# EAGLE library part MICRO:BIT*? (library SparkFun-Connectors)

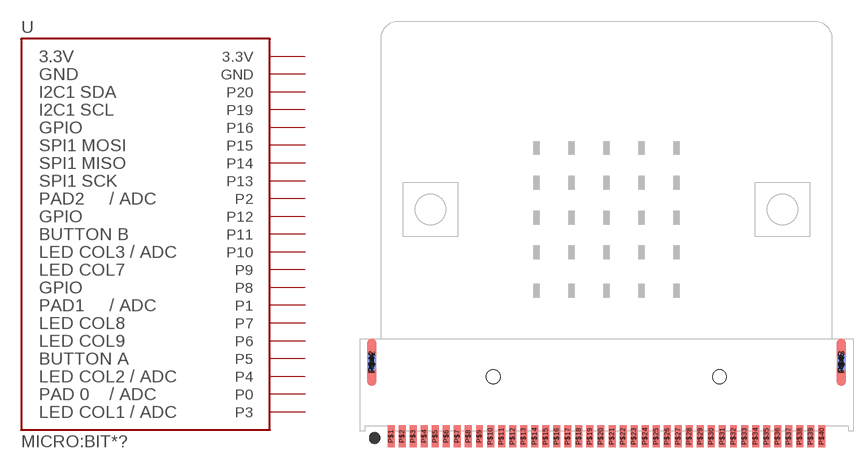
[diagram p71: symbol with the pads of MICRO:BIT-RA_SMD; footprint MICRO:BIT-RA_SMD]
Designator prefix U

## MICRO:BIT_RA (PROD_ID: CONN-14679; VALUE: micro:bit)  [MICRO:BIT-RA_SMD]
P$1  P3
P$2  P0
P$3  P0
P$4  P0
P$5  P0
P$6  P4
P$7  P5
P$8  P6
P$9  P7
P$10  P1
P$11  P1
P$12  P1
P$13  P1
P$14  P8
P$15  P9
P$16  P10
P$17  P11
P$18  P12
P$19  P2
P$20  P2
P$21  P2
P$22  P2
P$23  P13
P$24  P14
P$25  P15
P$26  P16
P$27  3.3V
P$28  3.3V
P$29  3.3V
P$30  3.3V
P$31  3.3V
P$32  3.3V
P$33  P19
P$34  P20
P$35  GND
P$36  GND
P$37  GND
P$38  GND
P$39  GND
P$40  GND

## Footprint MICRO:BIT-RA_SMD (pad centres in mm)
smd 0.8 x 2.5: P$1 -24.765,-6.15; P$2 -23.495,-6.15; P$3 -22.225,-6.15; P$4 -20.955,-6.15; P$5 -19.685,-6.15; P$6 -18.415,-6.15; P$7 -17.145,-6.15; P$8 -15.875,-6.15; P$9 -14.605,-6.15; P$10 -13.335,-6.15; P$11 -12.065,-6.15; P$12 -10.795,-6.15; P$13 -9.525,-6.15; P$14 -8.255,-6.15; P$15 -6.985,-6.15; P$16 -5.715,-6.15; P$17 -4.445,-6.15; P$18 -3.175,-6.15; P$19 -1.905,-6.15; P$20 -0.635,-6.15; P$21 0.635,-6.15; P$22 1.905,-6.15; P$23 3.175,-6.15; P$24 4.445,-6.15; P$25 5.715,-6.15; P$26 6.985,-6.15; P$27 8.255,-6.15; P$28 9.525,-6.15; P$29 10.795,-6.15; P$30 12.065,-6.15; P$31 13.335,-6.15; P$32 14.605,-6.15; P$33 15.875,-6.15; P$34 17.145,-6.15; P$35 18.415,-6.15; P$36 19.685,-6.15; P$37 20.955,-6.15; P$38 22.225,-6.15; P$39 23.495,-6.15; P$40 24.765,-6.15
smd 1.1 x 5.5: P$42 -27,2.36; P$43 27,2.36
smd 1.1 x 2 bottom: P$44 -27,2.36; P$45 27,2.36
hole 1.6 at 13,0.7
hole 1.6 at -13,0.7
